VERSION 5.4 ;
NAMESCASESENSITIVE ON ;
BUSBITCHARS "[]" ;
DIVIDERCHAR "/" ;
UNITS
  DATABASE MICRONS 1000 ;
END UNITS
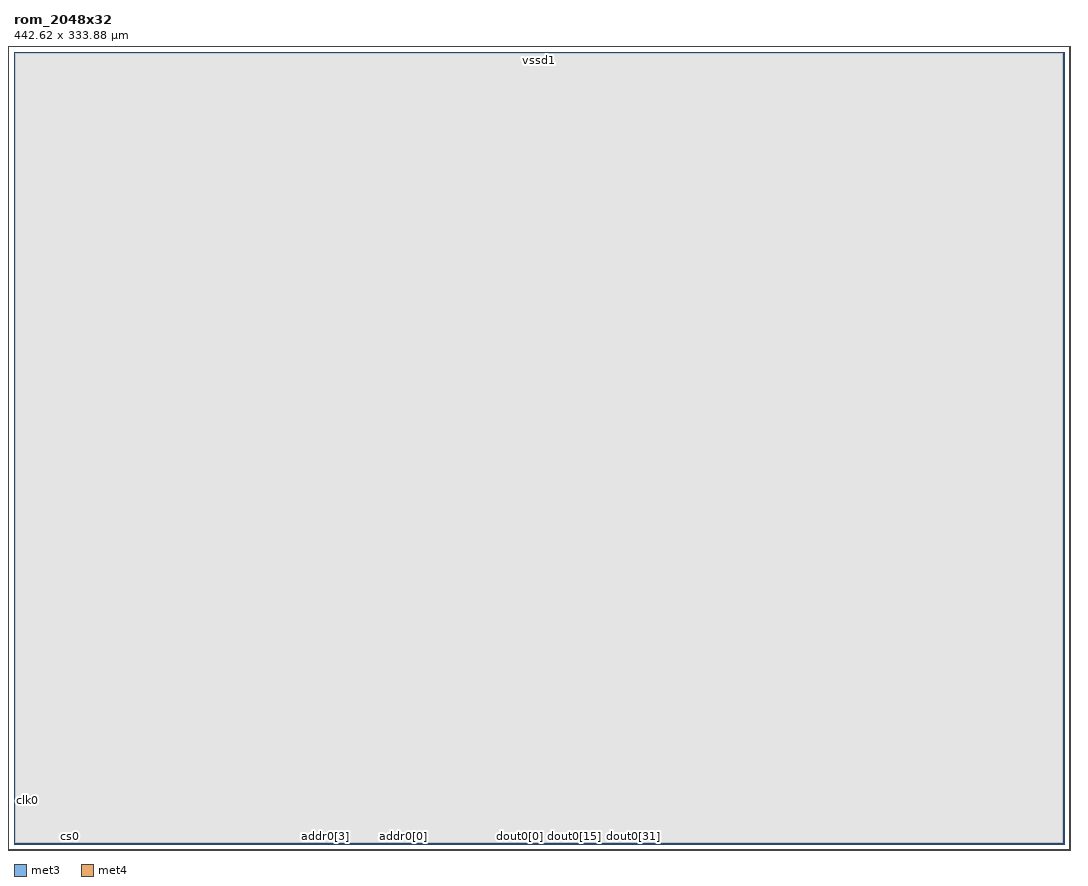
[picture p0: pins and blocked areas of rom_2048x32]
MACRO rom_2048x32
   CLASS BLOCK ;
   SIZE 442.62 BY 333.88 ;
   SYMMETRY X Y R90 ;
   PIN clk0
      DIRECTION INPUT ;
      PORT
         LAYER met3 ;
         RECT  -7.48 18.03 -7.1 18.41 ;
      END
   END clk0
   PIN cs0
      DIRECTION INPUT ;
      PORT
         LAYER met4 ;
         RECT  23.375 -7.48 23.755 -7.1 ;
      END
   END cs0
   PIN addr0[0]
      DIRECTION INPUT ;
      PORT
         LAYER met4 ;
         RECT  163.8 -7.48 164.18 -7.1 ;
      END
   END addr0[0]
   PIN addr0[1]
      DIRECTION INPUT ;
      PORT
         LAYER met4 ;
         RECT  165.84 -7.48 166.22 -7.1 ;
      END
   END addr0[1]
   PIN addr0[2]
      DIRECTION INPUT ;
      PORT
         LAYER met4 ;
         RECT  167.88 -7.48 168.26 -7.1 ;
      END
   END addr0[2]
   PIN addr0[3]
      DIRECTION INPUT ;
      PORT
         LAYER met4 ;
         RECT  131.11 -7.48 131.49 -7.1 ;
      END
   END addr0[3]
   PIN addr0[4]
      DIRECTION INPUT ;
      PORT
         LAYER met4 ;
         RECT  133.15 -7.48 133.53 -7.1 ;
      END
   END addr0[4]
   PIN addr0[5]
      DIRECTION INPUT ;
      PORT
         LAYER met4 ;
         RECT  135.19 -7.48 135.57 -7.1 ;
      END
   END addr0[5]
   PIN addr0[6]
      DIRECTION INPUT ;
      PORT
         LAYER met4 ;
         RECT  137.23 -7.48 137.61 -7.1 ;
      END
   END addr0[6]
   PIN addr0[7]
      DIRECTION INPUT ;
      PORT
         LAYER met4 ;
         RECT  139.27 -7.48 139.65 -7.1 ;
      END
   END addr0[7]
   PIN addr0[8]
      DIRECTION INPUT ;
      PORT
         LAYER met4 ;
         RECT  141.31 -7.48 141.69 -7.1 ;
      END
   END addr0[8]
   PIN addr0[9]
      DIRECTION INPUT ;
      PORT
         LAYER met4 ;
         RECT  143.35 -7.48 143.73 -7.1 ;
      END
   END addr0[9]
   PIN addr0[10]
      DIRECTION INPUT ;
      PORT
         LAYER met4 ;
         RECT  145.39 -7.48 145.77 -7.1 ;
      END
   END addr0[10]
   PIN dout0[0]
      DIRECTION OUTPUT ;
      PORT
         LAYER met4 ;
         RECT  213.085 -7.48 213.465 -7.1 ;
      END
   END dout0[0]
   PIN dout0[1]
      DIRECTION OUTPUT ;
      PORT
         LAYER met4 ;
         RECT  214.625 -7.48 215.005 -7.1 ;
      END
   END dout0[1]
   PIN dout0[2]
      DIRECTION OUTPUT ;
      PORT
         LAYER met4 ;
         RECT  216.165 -7.48 216.545 -7.1 ;
      END
   END dout0[2]
   PIN dout0[3]
      DIRECTION OUTPUT ;
      PORT
         LAYER met4 ;
         RECT  217.705 -7.48 218.085 -7.1 ;
      END
   END dout0[3]
   PIN dout0[4]
      DIRECTION OUTPUT ;
      PORT
         LAYER met4 ;
         RECT  219.245 -7.48 219.625 -7.1 ;
      END
   END dout0[4]
   PIN dout0[5]
      DIRECTION OUTPUT ;
      PORT
         LAYER met4 ;
         RECT  220.785 -7.48 221.165 -7.1 ;
      END
   END dout0[5]
   PIN dout0[6]
      DIRECTION OUTPUT ;
      PORT
         LAYER met4 ;
         RECT  222.325 -7.48 222.705 -7.1 ;
      END
   END dout0[6]
   PIN dout0[7]
      DIRECTION OUTPUT ;
      PORT
         LAYER met4 ;
         RECT  223.865 -7.48 224.245 -7.1 ;
      END
   END dout0[7]
   PIN dout0[8]
      DIRECTION OUTPUT ;
      PORT
         LAYER met4 ;
         RECT  225.405 -7.48 225.785 -7.1 ;
      END
   END dout0[8]
   PIN dout0[9]
      DIRECTION OUTPUT ;
      PORT
         LAYER met4 ;
         RECT  226.945 -7.48 227.325 -7.1 ;
      END
   END dout0[9]
   PIN dout0[10]
      DIRECTION OUTPUT ;
      PORT
         LAYER met4 ;
         RECT  228.485 -7.48 228.865 -7.1 ;
      END
   END dout0[10]
   PIN dout0[11]
      DIRECTION OUTPUT ;
      PORT
         LAYER met4 ;
         RECT  230.025 -7.48 230.405 -7.1 ;
      END
   END dout0[11]
   PIN dout0[12]
      DIRECTION OUTPUT ;
      PORT
         LAYER met4 ;
         RECT  231.565 -7.48 231.945 -7.1 ;
      END
   END dout0[12]
   PIN dout0[13]
      DIRECTION OUTPUT ;
      PORT
         LAYER met4 ;
         RECT  233.105 -7.48 233.485 -7.1 ;
      END
   END dout0[13]
   PIN dout0[14]
      DIRECTION OUTPUT ;
      PORT
         LAYER met4 ;
         RECT  234.645 -7.48 235.025 -7.1 ;
      END
   END dout0[14]
   PIN dout0[15]
      DIRECTION OUTPUT ;
      PORT
         LAYER met4 ;
         RECT  236.185 -7.48 236.565 -7.1 ;
      END
   END dout0[15]
   PIN dout0[16]
      DIRECTION OUTPUT ;
      PORT
         LAYER met4 ;
         RECT  237.725 -7.48 238.105 -7.1 ;
      END
   END dout0[16]
   PIN dout0[17]
      DIRECTION OUTPUT ;
      PORT
         LAYER met4 ;
         RECT  239.265 -7.48 239.645 -7.1 ;
      END
   END dout0[17]
   PIN dout0[18]
      DIRECTION OUTPUT ;
      PORT
         LAYER met4 ;
         RECT  240.805 -7.48 241.185 -7.1 ;
      END
   END dout0[18]
   PIN dout0[19]
      DIRECTION OUTPUT ;
      PORT
         LAYER met4 ;
         RECT  242.345 -7.48 242.725 -7.1 ;
      END
   END dout0[19]
   PIN dout0[20]
      DIRECTION OUTPUT ;
      PORT
         LAYER met4 ;
         RECT  243.885 -7.48 244.265 -7.1 ;
      END
   END dout0[20]
   PIN dout0[21]
      DIRECTION OUTPUT ;
      PORT
         LAYER met4 ;
         RECT  245.425 -7.48 245.805 -7.1 ;
      END
   END dout0[21]
   PIN dout0[22]
      DIRECTION OUTPUT ;
      PORT
         LAYER met4 ;
         RECT  246.965 -7.48 247.345 -7.1 ;
      END
   END dout0[22]
   PIN dout0[23]
      DIRECTION OUTPUT ;
      PORT
         LAYER met4 ;
         RECT  248.505 -7.48 248.885 -7.1 ;
      END
   END dout0[23]
   PIN dout0[24]
      DIRECTION OUTPUT ;
      PORT
         LAYER met4 ;
         RECT  250.045 -7.48 250.425 -7.1 ;
      END
   END dout0[24]
   PIN dout0[25]
      DIRECTION OUTPUT ;
      PORT
         LAYER met4 ;
         RECT  251.585 -7.48 251.965 -7.1 ;
      END
   END dout0[25]
   PIN dout0[26]
      DIRECTION OUTPUT ;
      PORT
         LAYER met4 ;
         RECT  253.125 -7.48 253.505 -7.1 ;
      END
   END dout0[26]
   PIN dout0[27]
      DIRECTION OUTPUT ;
      PORT
         LAYER met4 ;
         RECT  254.665 -7.48 255.045 -7.1 ;
      END
   END dout0[27]
   PIN dout0[28]
      DIRECTION OUTPUT ;
      PORT
         LAYER met4 ;
         RECT  256.205 -7.48 256.585 -7.1 ;
      END
   END dout0[28]
   PIN dout0[29]
      DIRECTION OUTPUT ;
      PORT
         LAYER met4 ;
         RECT  257.745 -7.48 258.125 -7.1 ;
      END
   END dout0[29]
   PIN dout0[30]
      DIRECTION OUTPUT ;
      PORT
         LAYER met4 ;
         RECT  259.285 -7.48 259.665 -7.1 ;
      END
   END dout0[30]
   PIN dout0[31]
      DIRECTION OUTPUT ;
      PORT
         LAYER met4 ;
         RECT  260.825 -7.48 261.205 -7.1 ;
      END
   END dout0[31]
   PIN vccd1
      DIRECTION INOUT ;
      USE POWER ; 
      SHAPE ABUTMENT ; 
      PORT
         LAYER met3 ;
         RECT  -7.48 339.62 450.1 341.36 ;
         LAYER met3 ;
         RECT  -7.48 -7.48 450.1 -5.74 ;
         LAYER met4 ;
         RECT  -7.48 -7.48 -5.74 341.36 ;
         LAYER met4 ;
         RECT  448.36 -7.48 450.1 341.36 ;
      END
   END vccd1
   PIN vssd1
      DIRECTION INOUT ;
      USE GROUND ; 
      SHAPE ABUTMENT ; 
      PORT
         LAYER met3 ;
         RECT  -4.0 336.14 446.62 337.88 ;
         LAYER met3 ;
         RECT  -4.0 -4.0 446.62 -2.26 ;
         LAYER met4 ;
         RECT  444.88 -4.0 446.62 337.88 ;
         LAYER met4 ;
         RECT  -4.0 -4.0 -2.26 337.88 ;
      END
   END vssd1
   OBS
   LAYER  met1 ;
      RECT  0.62 0.62 442.0 333.26 ;
   LAYER  met2 ;
      RECT  0.62 0.62 442.0 333.26 ;
   LAYER  met3 ;
      RECT  0.62 0.62 442.0 333.26 ;
   LAYER  met4 ;
      RECT  0.62 0.62 442.0 333.26 ;
   END
END    rom_2048x32
END    LIBRARY
